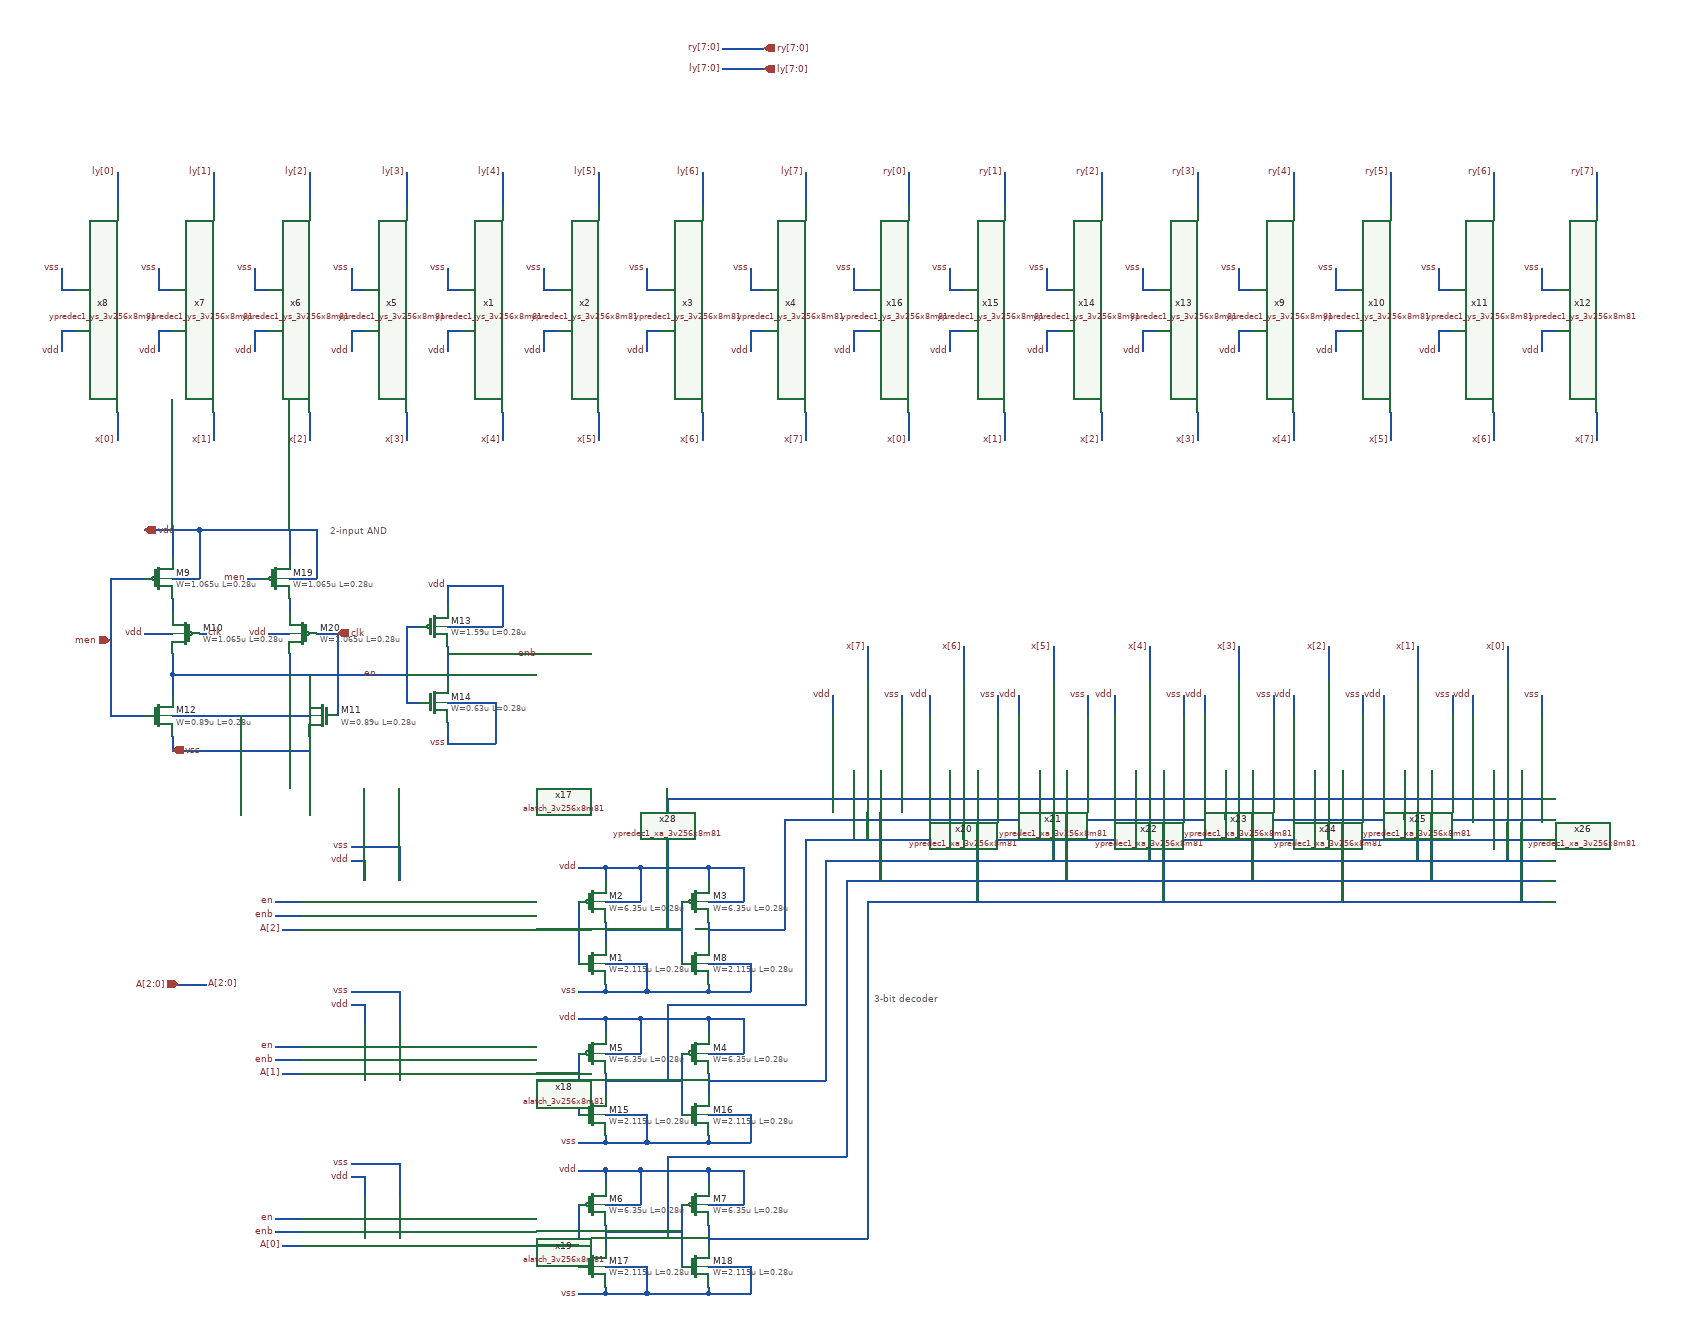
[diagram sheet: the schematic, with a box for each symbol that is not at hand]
v {xschem version=3.4.6 file_version=1.2}
G {}
K {}
V {}
S {}
E {}
T {2-input AND} -10 310 0 0 0.4 0.4 {}
T {3-bit decoder} 780 990 0 0 0.4 0.4 {}
N 1830 -200 1830 -150 {lab=ry[7]}
N 1680 -200 1680 -150 {lab=ry[6]}
N 1530 -200 1530 -150 {lab=ry[5]}
N 1390 -200 1390 -150 {lab=ry[4]}
N 1250 -200 1250 -150 {lab=ry[3]}
N 1110 -200 1110 -150 {lab=ry[2]}
N 970 -200 970 -150 {lab=ry[1]}
N 830 -200 830 -150 {lab=ry[0]}
N 680 -200 680 -150 {lab=ly[7]}
N 530 -200 530 -150 {lab=ly[6]}
N 380 -200 380 -150 {lab=ly[5]}
N 240 -200 240 -150 {lab=ly[4]}
N 100 -200 100 -150 {lab=ly[3]}
N -40 -200 -40 -150 {lab=ly[2]}
N -180 -200 -180 -150 {lab=ly[1]}
N -320 -200 -320 -150 {lab=ly[0]}
N -400 -30 -380 -30 {lab=vss}
N -400 -60 -400 -30 {lab=vss}
N -400 30 -380 30 {lab=vdd}
N -400 30 -400 60 {lab=vdd}
N -260 -30 -240 -30 {lab=vss}
N -260 -60 -260 -30 {lab=vss}
N -260 30 -240 30 {lab=vdd}
N -260 30 -260 60 {lab=vdd}
N -120 -30 -100 -30 {lab=vss}
N -120 -60 -120 -30 {lab=vss}
N -120 30 -100 30 {lab=vdd}
N -120 30 -120 60 {lab=vdd}
N 20 -30 40 -30 {lab=vss}
N 20 -60 20 -30 {lab=vss}
N 20 30 40 30 {lab=vdd}
N 20 30 20 60 {lab=vdd}
N 160 -30 180 -30 {lab=vss}
N 160 -60 160 -30 {lab=vss}
N 160 30 180 30 {lab=vdd}
N 160 30 160 60 {lab=vdd}
N 300 -30 320 -30 {lab=vss}
N 300 -60 300 -30 {lab=vss}
N 300 30 320 30 {lab=vdd}
N 300 30 300 60 {lab=vdd}
N 450 -30 470 -30 {lab=vss}
N 450 -60 450 -30 {lab=vss}
N 450 30 470 30 {lab=vdd}
N 450 30 450 60 {lab=vdd}
N 600 -30 620 -30 {lab=vss}
N 600 -60 600 -30 {lab=vss}
N 600 30 620 30 {lab=vdd}
N 600 30 600 60 {lab=vdd}
N 750 -30 770 -30 {lab=vss}
N 750 -60 750 -30 {lab=vss}
N 750 30 770 30 {lab=vdd}
N 750 30 750 60 {lab=vdd}
N 890 -30 910 -30 {lab=vss}
N 890 -60 890 -30 {lab=vss}
N 890 30 910 30 {lab=vdd}
N 890 30 890 60 {lab=vdd}
N 1030 -30 1050 -30 {lab=vss}
N 1030 -60 1030 -30 {lab=vss}
N 1030 30 1050 30 {lab=vdd}
N 1030 30 1030 60 {lab=vdd}
N 1170 -30 1190 -30 {lab=vss}
N 1170 -60 1170 -30 {lab=vss}
N 1170 30 1190 30 {lab=vdd}
N 1170 30 1170 60 {lab=vdd}
N 1310 -30 1330 -30 {lab=vss}
N 1310 -60 1310 -30 {lab=vss}
N 1310 30 1330 30 {lab=vdd}
N 1310 30 1310 60 {lab=vdd}
N 1450 -30 1470 -30 {lab=vss}
N 1450 -60 1450 -30 {lab=vss}
N 1450 30 1470 30 {lab=vdd}
N 1450 30 1450 60 {lab=vdd}
N 1600 -30 1620 -30 {lab=vss}
N 1600 -60 1600 -30 {lab=vss}
N 1600 30 1620 30 {lab=vdd}
N 1600 30 1600 60 {lab=vdd}
N 1750 -30 1770 -30 {lab=vss}
N 1750 -60 1750 -30 {lab=vss}
N 1750 30 1770 30 {lab=vdd}
N 1750 30 1750 60 {lab=vdd}
N -80 900 -50 900 {lab=A[2]}
N -80 1110 -50 1110 {lab=A[1]}
N -230 980 -190 980 {lab=A[2:0]}
N 770 490 770 540 {lab=x[7]}
N 910 490 910 540 {lab=x[6]}
N 1040 490 1040 540 {lab=x[5]}
N 1180 490 1180 540 {lab=x[4]}
N 350 860 350 950 {lab=#net1}
N 390 810 390 830 {lab=vdd}
N 390 810 440 810 {lab=vdd}
N 440 810 440 860 {lab=vdd}
N 390 860 440 860 {lab=vdd}
N 390 950 450 950 {lab=vss}
N 450 950 450 990 {lab=vss}
N 390 990 450 990 {lab=vss}
N 390 980 390 990 {lab=vss}
N 390 890 390 920 {lab=#net2}
N 390 900 500 900 {lab=#net2}
N 500 860 500 950 {lab=#net2}
N 540 810 540 830 {lab=vdd}
N 540 810 590 810 {lab=vdd}
N 590 810 590 860 {lab=vdd}
N 540 860 590 860 {lab=vdd}
N 540 950 600 950 {lab=vss}
N 600 950 600 990 {lab=vss}
N 540 990 600 990 {lab=vss}
N 540 980 540 990 {lab=vss}
N 540 890 540 920 {lab=#net3}
N 540 900 650 900 {lab=#net3}
N 160 900 350 900 {lab=#net1}
N 440 810 540 810 {lab=vdd}
N 450 990 540 990 {lab=vss}
N 350 990 390 990 {lab=vss}
N 350 810 390 810 {lab=vdd}
N 350 1080 350 1170 {lab=#net4}
N 390 1030 390 1050 {lab=vdd}
N 390 1030 440 1030 {lab=vdd}
N 440 1030 440 1080 {lab=vdd}
N 390 1080 440 1080 {lab=vdd}
N 390 1170 450 1170 {lab=vss}
N 450 1170 450 1210 {lab=vss}
N 390 1210 450 1210 {lab=vss}
N 390 1200 390 1210 {lab=vss}
N 390 1110 390 1140 {lab=#net5}
N 390 1120 500 1120 {lab=#net5}
N 500 1080 500 1170 {lab=#net5}
N 540 1030 540 1050 {lab=vdd}
N 540 1030 590 1030 {lab=vdd}
N 590 1030 590 1080 {lab=vdd}
N 540 1080 590 1080 {lab=vdd}
N 540 1170 600 1170 {lab=vss}
N 600 1170 600 1210 {lab=vss}
N 540 1210 600 1210 {lab=vss}
N 540 1200 540 1210 {lab=vss}
N 540 1110 540 1140 {lab=#net6}
N 540 1120 650 1120 {lab=#net6}
N 440 1030 540 1030 {lab=vdd}
N 450 1210 540 1210 {lab=vss}
N 350 1210 390 1210 {lab=vss}
N 350 1030 390 1030 {lab=vdd}
N 160 1110 350 1110 {lab=#net4}
N -90 860 -50 860 {lab=en}
N -90 1070 -50 1070 {lab=en}
N -90 880 -50 880 {lab=enb}
N -90 1090 -50 1090 {lab=enb}
N 160 490 160 540 {lab=enb}
N 100 460 120 460 {lab=en}
N 100 460 100 570 {lab=en}
N 100 570 120 570 {lab=en}
N 160 500 260 500 {lab=enb}
N 160 600 160 630 {lab=vss}
N 160 630 230 630 {lab=vss}
N 230 570 230 630 {lab=vss}
N 160 570 230 570 {lab=vss}
N 160 400 160 430 {lab=vdd}
N 160 400 240 400 {lab=vdd}
N 240 400 240 460 {lab=vdd}
N 160 460 240 460 {lab=vdd}
N 40 800 40 830 {lab=vdd}
N 20 800 40 800 {lab=vdd}
N 90 780 90 830 {lab=vss}
N 20 780 90 780 {lab=vss}
N 40 1010 40 1040 {lab=vdd}
N 20 1010 40 1010 {lab=vdd}
N 90 990 90 1040 {lab=vss}
N 20 990 90 990 {lab=vss}
N 720 560 720 590 {lab=vdd}
N 820 560 820 590 {lab=vss}
N 860 560 860 590 {lab=vdd}
N 960 560 960 590 {lab=vss}
N 990 560 990 590 {lab=vdd}
N 1090 560 1090 590 {lab=vss}
N 1130 560 1130 590 {lab=vdd}
N 1230 560 1230 590 {lab=vss}
N -240 420 -240 440 {lab=#net7}
N -240 320 -240 360 {lab=vdd}
N -240 390 -200 390 {lab=vdd}
N -200 320 -200 390 {lab=vdd}
N -280 320 -200 320 {lab=vdd}
N -330 390 -330 590 {lab=men}
N -240 620 -240 640 {lab=vss}
N -240 640 -40 640 {lab=vss}
N -40 620 -40 640 {lab=vss}
N -240 590 -40 590 {lab=vss}
N -140 590 -140 640 {lab=vss}
N 0 470 0 590 {lab=clk}
N -240 530 -240 560 {lab=en}
N -240 530 100 530 {lab=en}
N -40 530 -40 560 {lab=en}
N -240 500 -240 530 {lab=en}
N 480 710 480 900 {lab=#net2}
N 650 740 650 900 {lab=#net3}
N 480 1010 480 1120 {lab=#net5}
N 480 1010 680 1010 {lab=#net5}
N 680 770 680 1010 {lab=#net5}
N 650 1120 710 1120 {lab=#net6}
N 710 810 710 1120 {lab=#net6}
N 710 800 710 810 {lab=#net6}
N 560 -350 620 -350 {lab=ly[7:0]}
N -80 1360 -50 1360 {lab=A[0]}
N -90 1320 -50 1320 {lab=en}
N -90 1340 -50 1340 {lab=enb}
N 40 1260 40 1290 {lab=vdd}
N 20 1260 40 1260 {lab=vdd}
N 90 1240 90 1290 {lab=vss}
N 20 1240 90 1240 {lab=vss}
N 350 1300 350 1390 {lab=#net8}
N 390 1250 390 1270 {lab=vdd}
N 390 1250 440 1250 {lab=vdd}
N 440 1250 440 1300 {lab=vdd}
N 390 1300 440 1300 {lab=vdd}
N 390 1390 450 1390 {lab=vss}
N 450 1390 450 1430 {lab=vss}
N 390 1430 450 1430 {lab=vss}
N 390 1420 390 1430 {lab=vss}
N 390 1330 390 1360 {lab=#net9}
N 390 1340 500 1340 {lab=#net9}
N 500 1300 500 1390 {lab=#net9}
N 540 1250 540 1270 {lab=vdd}
N 540 1250 590 1250 {lab=vdd}
N 590 1250 590 1300 {lab=vdd}
N 540 1300 590 1300 {lab=vdd}
N 540 1390 600 1390 {lab=vss}
N 600 1390 600 1430 {lab=vss}
N 540 1430 600 1430 {lab=vss}
N 540 1420 540 1430 {lab=vss}
N 540 1330 540 1360 {lab=#net10}
N 440 1250 540 1250 {lab=vdd}
N 450 1430 540 1430 {lab=vss}
N 350 1430 390 1430 {lab=vss}
N 350 1250 390 1250 {lab=vdd}
N 160 1360 350 1360 {lab=#net8}
N 480 1230 480 1340 {lab=#net9}
N 740 830 740 1230 {lab=#net9}
N 480 1230 740 1230 {lab=#net9}
N 770 860 770 1350 {lab=#net10}
N 540 1350 770 1350 {lab=#net10}
N 1310 490 1310 540 {lab=x[3]}
N 1260 560 1260 590 {lab=vdd}
N 1360 560 1360 590 {lab=vss}
N 1440 490 1440 540 {lab=x[2]}
N 1390 560 1390 590 {lab=vdd}
N 1490 560 1490 590 {lab=vss}
N 1570 490 1570 540 {lab=x[1]}
N 1520 560 1520 590 {lab=vdd}
N 1620 560 1620 590 {lab=vss}
N 1700 490 1700 540 {lab=x[0]}
N 1650 560 1650 590 {lab=vdd}
N 1750 560 1750 590 {lab=vss}
N 770 860 1750 860 {lab=#net10}
N 740 830 1750 830 {lab=#net9}
N 710 800 1750 800 {lab=#net6}
N 680 770 1750 770 {lab=#net5}
N 650 740 1750 740 {lab=#net3}
N 480 710 1750 710 {lab=#net2}
N 750 670 750 710 {lab=#net2}
N 770 670 770 770 {lab=#net5}
N 790 670 790 830 {lab=#net9}
N 890 670 890 710 {lab=#net2}
N 910 670 910 770 {lab=#net5}
N 930 670 930 860 {lab=#net10}
N 1020 670 1020 710 {lab=#net2}
N 1040 670 1040 800 {lab=#net6}
N 1060 670 1060 830 {lab=#net9}
N 1160 670 1160 710 {lab=#net2}
N 1180 670 1180 800 {lab=#net6}
N 1200 670 1200 860 {lab=#net10}
N 1290 670 1290 740 {lab=#net3}
N 1420 670 1420 740 {lab=#net3}
N 1550 670 1550 740 {lab=#net3}
N 1680 670 1680 740 {lab=#net3}
N 1310 670 1310 770 {lab=#net5}
N 1330 670 1330 830 {lab=#net9}
N 1440 670 1440 770 {lab=#net5}
N 1460 670 1460 860 {lab=#net10}
N 1570 670 1570 800 {lab=#net6}
N 1590 670 1590 830 {lab=#net9}
N 1700 670 1700 800 {lab=#net6}
N 1720 670 1720 860 {lab=#net10}
N 560 -380 620 -380 {lab=ry[7:0]}
N 680 150 680 190 {lab=x[7]}
N 530 150 530 190 {lab=x[6]}
N 380 150 380 190 {lab=x[5]}
N 240 150 240 190 {lab=x[4]}
N 100 150 100 190 {lab=x[3]}
N -40 150 -40 190 {lab=x[2]}
N -180 150 -180 190 {lab=x[1]}
N -320 150 -320 190 {lab=x[0]}
N 1830 150 1830 190 {lab=x[7]}
N 1680 150 1680 190 {lab=x[6]}
N 1530 150 1530 190 {lab=x[5]}
N 1390 150 1390 190 {lab=x[4]}
N 1250 150 1250 190 {lab=x[3]}
N 1110 150 1110 190 {lab=x[2]}
N 970 150 970 190 {lab=x[1]}
N 830 150 830 190 {lab=x[0]}
N -280 470 -240 470 {lab=vdd}
N -330 590 -280 590 {lab=men}
N -330 390 -280 390 {lab=men}
N -70 420 -70 440 {lab=#net11}
N -70 320 -70 360 {lab=vdd}
N -70 390 -30 390 {lab=vdd}
N -30 320 -30 390 {lab=vdd}
N -130 390 -110 390 {lab=men}
N -200 470 -190 470 {lab=clk}
N -100 470 -70 470 {lab=vdd}
N -70 500 -70 530 {lab=en}
N -200 320 -30 320 {lab=vdd}
N -30 470 -0 470 {lab=clk}
C {ypredec1_ys_3v256x8m81.sym} 230 0 3 0 {name=x1}
C {ypredec1_ys_3v256x8m81.sym} 370 0 3 0 {name=x2}
C {ypredec1_ys_3v256x8m81.sym} 520 0 3 0 {name=x3}
C {ypredec1_ys_3v256x8m81.sym} 670 0 3 0 {name=x4}
C {ypredec1_ys_3v256x8m81.sym} 90 0 3 0 {name=x5}
C {ypredec1_ys_3v256x8m81.sym} -50 0 3 0 {name=x6}
C {ypredec1_ys_3v256x8m81.sym} -190 0 3 0 {name=x7}
C {ypredec1_ys_3v256x8m81.sym} -330 0 3 0 {name=x8}
C {ypredec1_ys_3v256x8m81.sym} 1380 0 3 0 {name=x9}
C {ypredec1_ys_3v256x8m81.sym} 1520 0 3 0 {name=x10}
C {ypredec1_ys_3v256x8m81.sym} 1670 0 3 0 {name=x11}
C {ypredec1_ys_3v256x8m81.sym} 1820 0 3 0 {name=x12}
C {ypredec1_ys_3v256x8m81.sym} 1240 0 3 0 {name=x13}
C {ypredec1_ys_3v256x8m81.sym} 1100 0 3 0 {name=x14}
C {ypredec1_ys_3v256x8m81.sym} 960 0 3 0 {name=x15}
C {ypredec1_ys_3v256x8m81.sym} 820 0 3 0 {name=x16}
C {lab_pin.sym} 1830 -200 1 0 {name=p1 sig_type=std_logic lab=ry[7]}
C {lab_pin.sym} 1680 -200 1 0 {name=p2 sig_type=std_logic lab=ry[6]}
C {lab_pin.sym} 1530 -200 1 0 {name=p3 sig_type=std_logic lab=ry[5]}
C {lab_pin.sym} 1390 -200 1 0 {name=p4 sig_type=std_logic lab=ry[4]}
C {lab_pin.sym} 1250 -200 1 0 {name=p5 sig_type=std_logic lab=ry[3]}
C {lab_pin.sym} 1110 -200 1 0 {name=p6 sig_type=std_logic lab=ry[2]}
C {lab_pin.sym} 970 -200 1 0 {name=p7 sig_type=std_logic lab=ry[1]}
C {lab_pin.sym} 830 -200 1 0 {name=p8 sig_type=std_logic lab=ry[0]}
C {lab_pin.sym} 680 -200 1 0 {name=p9 sig_type=std_logic lab=ly[7]}
C {lab_pin.sym} 530 -200 1 0 {name=p10 sig_type=std_logic lab=ly[6]}
C {lab_pin.sym} 380 -200 1 0 {name=p11 sig_type=std_logic lab=ly[5]}
C {lab_pin.sym} 240 -200 1 0 {name=p12 sig_type=std_logic lab=ly[4]}
C {lab_pin.sym} 100 -200 1 0 {name=p13 sig_type=std_logic lab=ly[3]}
C {lab_pin.sym} -40 -200 1 0 {name=p14 sig_type=std_logic lab=ly[2]}
C {lab_pin.sym} -180 -200 1 0 {name=p15 sig_type=std_logic lab=ly[1]}
C {lab_pin.sym} -320 -200 1 0 {name=p16 sig_type=std_logic lab=ly[0]}
C {lab_pin.sym} -400 -60 1 0 {name=p17 sig_type=std_logic lab=vss}
C {lab_pin.sym} -400 60 3 0 {name=p18 sig_type=std_logic lab=vdd}
C {lab_pin.sym} -260 -60 1 0 {name=p19 sig_type=std_logic lab=vss}
C {lab_pin.sym} -260 60 3 0 {name=p20 sig_type=std_logic lab=vdd}
C {lab_pin.sym} -120 -60 1 0 {name=p21 sig_type=std_logic lab=vss}
C {lab_pin.sym} -120 60 3 0 {name=p22 sig_type=std_logic lab=vdd}
C {lab_pin.sym} 20 -60 1 0 {name=p23 sig_type=std_logic lab=vss}
C {lab_pin.sym} 20 60 3 0 {name=p24 sig_type=std_logic lab=vdd}
C {lab_pin.sym} 160 -60 1 0 {name=p25 sig_type=std_logic lab=vss}
C {lab_pin.sym} 160 60 3 0 {name=p26 sig_type=std_logic lab=vdd}
C {lab_pin.sym} 300 -60 1 0 {name=p27 sig_type=std_logic lab=vss}
C {lab_pin.sym} 300 60 3 0 {name=p28 sig_type=std_logic lab=vdd}
C {lab_pin.sym} 450 -60 1 0 {name=p29 sig_type=std_logic lab=vss}
C {lab_pin.sym} 450 60 3 0 {name=p30 sig_type=std_logic lab=vdd}
C {lab_pin.sym} 600 -60 1 0 {name=p31 sig_type=std_logic lab=vss}
C {lab_pin.sym} 600 60 3 0 {name=p32 sig_type=std_logic lab=vdd}
C {lab_pin.sym} 750 -60 1 0 {name=p33 sig_type=std_logic lab=vss}
C {lab_pin.sym} 750 60 3 0 {name=p34 sig_type=std_logic lab=vdd}
C {lab_pin.sym} 890 -60 1 0 {name=p35 sig_type=std_logic lab=vss}
C {lab_pin.sym} 890 60 3 0 {name=p36 sig_type=std_logic lab=vdd}
C {lab_pin.sym} 1030 -60 1 0 {name=p37 sig_type=std_logic lab=vss}
C {lab_pin.sym} 1030 60 3 0 {name=p38 sig_type=std_logic lab=vdd}
C {lab_pin.sym} 1170 -60 1 0 {name=p39 sig_type=std_logic lab=vss}
C {lab_pin.sym} 1170 60 3 0 {name=p40 sig_type=std_logic lab=vdd}
C {lab_pin.sym} 1310 -60 1 0 {name=p41 sig_type=std_logic lab=vss}
C {lab_pin.sym} 1310 60 3 0 {name=p42 sig_type=std_logic lab=vdd}
C {lab_pin.sym} 1450 -60 1 0 {name=p43 sig_type=std_logic lab=vss}
C {lab_pin.sym} 1450 60 3 0 {name=p44 sig_type=std_logic lab=vdd}
C {lab_pin.sym} 1600 -60 1 0 {name=p45 sig_type=std_logic lab=vss}
C {lab_pin.sym} 1600 60 3 0 {name=p46 sig_type=std_logic lab=vdd}
C {lab_pin.sym} 1750 -60 1 0 {name=p47 sig_type=std_logic lab=vss}
C {lab_pin.sym} 1750 60 3 0 {name=p48 sig_type=std_logic lab=vdd}
C {alatch_3v256x8m81.sym} 100 880 0 0 {name=x17}
C {alatch_3v256x8m81.sym} 100 1090 0 0 {name=x18}
C {lab_pin.sym} -80 900 0 0 {name=p49 sig_type=std_logic lab=A[2]}
C {lab_pin.sym} -80 1110 0 0 {name=p50 sig_type=std_logic lab=A[1]}
C {ipin.sym} -230 980 0 0 {name=p51 lab=A[2:0]}
C {lab_pin.sym} -190 980 0 1 {name=p52 sig_type=std_logic lab=A[2:0]}
C {lab_pin.sym} 770 490 1 0 {name=p53 sig_type=std_logic lab=x[7]}
C {lab_pin.sym} 910 490 1 0 {name=p54 sig_type=std_logic lab=x[6]}
C {lab_pin.sym} 1040 490 1 0 {name=p55 sig_type=std_logic lab=x[5]}
C {lab_pin.sym} 1180 490 1 0 {name=p56 sig_type=std_logic lab=x[4]}
C {symbols/nfet_03v3.sym} 370 950 0 0 {name=M1
L=0.28u
W=2.115u
nf=1
m=1
ad="'int((nf+1)/2) * W/nf * 0.18u'"
pd="'2*int((nf+1)/2) * (W/nf + 0.18u)'"
as="'int((nf+2)/2) * W/nf * 0.18u'"
ps="'2*int((nf+2)/2) * (W/nf + 0.18u)'"
nrd="'0.18u / W'" nrs="'0.18u / W'"
sa=0 sb=0 sd=0
model=nfet_03v3
spiceprefix=X
}
C {symbols/pfet_03v3.sym} 370 860 0 0 {name=M2
L=0.28u
W=6.35u
nf=1
m=1
ad="'int((nf+1)/2) * W/nf * 0.18u'"
pd="'2*int((nf+1)/2) * (W/nf + 0.18u)'"
as="'int((nf+2)/2) * W/nf * 0.18u'"
ps="'2*int((nf+2)/2) * (W/nf + 0.18u)'"
nrd="'0.18u / W'" nrs="'0.18u / W'"
sa=0 sb=0 sd=0
model=pfet_03v3
spiceprefix=X
}
C {lab_pin.sym} 350 810 0 0 {name=p57 sig_type=std_logic lab=vdd}
C {lab_pin.sym} 350 990 0 0 {name=p58 sig_type=std_logic lab=vss}
C {lab_pin.sym} 350 1030 0 0 {name=p59 sig_type=std_logic lab=vdd}
C {lab_pin.sym} 350 1210 0 0 {name=p60 sig_type=std_logic lab=vss}
C {symbols/pfet_03v3.sym} -260 390 0 0 {name=M9
L=0.28u
W=1.065u
nf=1
m=1
ad="'int((nf+1)/2) * W/nf * 0.18u'"
pd="'2*int((nf+1)/2) * (W/nf + 0.18u)'"
as="'int((nf+2)/2) * W/nf * 0.18u'"
ps="'2*int((nf+2)/2) * (W/nf + 0.18u)'"
nrd="'0.18u / W'" nrs="'0.18u / W'"
sa=0 sb=0 sd=0
model=pfet_03v3
spiceprefix=X
}
C {symbols/pfet_03v3.sym} -220 470 0 1 {name=M10
L=0.28u
W=1.065u
nf=1
m=1
ad="'int((nf+1)/2) * W/nf * 0.18u'"
pd="'2*int((nf+1)/2) * (W/nf + 0.18u)'"
as="'int((nf+2)/2) * W/nf * 0.18u'"
ps="'2*int((nf+2)/2) * (W/nf + 0.18u)'"
nrd="'0.18u / W'" nrs="'0.18u / W'"
sa=0 sb=0 sd=0
model=pfet_03v3
spiceprefix=X
}
C {symbols/nfet_03v3.sym} -20 590 0 1 {name=M11
L=0.28u
W=0.89u
nf=1
m=1
ad="'int((nf+1)/2) * W/nf * 0.18u'"
pd="'2*int((nf+1)/2) * (W/nf + 0.18u)'"
as="'int((nf+2)/2) * W/nf * 0.18u'"
ps="'2*int((nf+2)/2) * (W/nf + 0.18u)'"
nrd="'0.18u / W'" nrs="'0.18u / W'"
sa=0 sb=0 sd=0
model=nfet_03v3
spiceprefix=X
}
C {symbols/nfet_03v3.sym} -260 590 0 0 {name=M12
L=0.28u
W=0.89u
nf=1
m=1
ad="'int((nf+1)/2) * W/nf * 0.18u'"
pd="'2*int((nf+1)/2) * (W/nf + 0.18u)'"
as="'int((nf+2)/2) * W/nf * 0.18u'"
ps="'2*int((nf+2)/2) * (W/nf + 0.18u)'"
nrd="'0.18u / W'" nrs="'0.18u / W'"
sa=0 sb=0 sd=0
model=nfet_03v3
spiceprefix=X
}
C {ipin.sym} 0 470 0 1 {name=p61 lab=clk}
C {ipin.sym} -330 480 0 0 {name=p62 lab=men}
C {lab_pin.sym} -90 860 0 0 {name=p63 sig_type=std_logic lab=en}
C {lab_pin.sym} -90 1070 0 0 {name=p64 sig_type=std_logic lab=en}
C {lab_pin.sym} -90 880 0 0 {name=p65 sig_type=std_logic lab=enb}
C {lab_pin.sym} -90 1090 0 0 {name=p66 sig_type=std_logic lab=enb}
C {lab_wire.sym} 60 530 0 0 {name=p67 sig_type=std_logic lab=en}
C {symbols/pfet_03v3.sym} 140 460 0 0 {name=M13
L=0.28u
W=1.59u
nf=2
m=1
ad="'int((nf+1)/2) * W/nf * 0.18u'"
pd="'2*int((nf+1)/2) * (W/nf + 0.18u)'"
as="'int((nf+2)/2) * W/nf * 0.18u'"
ps="'2*int((nf+2)/2) * (W/nf + 0.18u)'"
nrd="'0.18u / W'" nrs="'0.18u / W'"
sa=0 sb=0 sd=0
model=pfet_03v3
spiceprefix=X
}
C {symbols/nfet_03v3.sym} 140 570 0 0 {name=M14
L=0.28u
W=0.63u
nf=1
m=1
ad="'int((nf+1)/2) * W/nf * 0.18u'"
pd="'2*int((nf+1)/2) * (W/nf + 0.18u)'"
as="'int((nf+2)/2) * W/nf * 0.18u'"
ps="'2*int((nf+2)/2) * (W/nf + 0.18u)'"
nrd="'0.18u / W'" nrs="'0.18u / W'"
sa=0 sb=0 sd=0
model=nfet_03v3
spiceprefix=X
}
C {lab_pin.sym} 260 500 0 1 {name=p68 sig_type=std_logic lab=enb}
C {lab_pin.sym} 160 400 0 0 {name=p69 sig_type=std_logic lab=vdd}
C {lab_pin.sym} 160 630 0 0 {name=p70 sig_type=std_logic lab=vss}
C {lab_pin.sym} 20 780 0 0 {name=p71 sig_type=std_logic lab=vss}
C {lab_pin.sym} 20 990 0 0 {name=p72 sig_type=std_logic lab=vss}
C {lab_pin.sym} 20 800 0 0 {name=p73 sig_type=std_logic lab=vdd}
C {lab_pin.sym} 20 1010 0 0 {name=p74 sig_type=std_logic lab=vdd}
C {lab_pin.sym} 720 560 1 0 {name=p75 sig_type=std_logic lab=vdd}
C {lab_pin.sym} 860 560 1 0 {name=p76 sig_type=std_logic lab=vdd}
C {lab_pin.sym} 990 560 1 0 {name=p77 sig_type=std_logic lab=vdd}
C {lab_pin.sym} 1130 560 1 0 {name=p78 sig_type=std_logic lab=vdd}
C {lab_pin.sym} 820 560 1 0 {name=p79 sig_type=std_logic lab=vss}
C {lab_pin.sym} 960 560 1 0 {name=p80 sig_type=std_logic lab=vss}
C {lab_pin.sym} 1090 560 1 0 {name=p81 sig_type=std_logic lab=vss}
C {lab_pin.sym} 1230 560 1 0 {name=p82 sig_type=std_logic lab=vss}
C {opin.sym} 620 -350 0 0 {name=p83 lab=ly[7:0]}
C {lab_pin.sym} 560 -350 0 0 {name=p84 sig_type=std_logic lab=ly[7:0]}
C {iopin.sym} -280 320 0 1 {name=p85 lab=vdd}
C {iopin.sym} -240 640 0 1 {name=p86 lab=vss}
C {alatch_3v256x8m81.sym} 100 1340 0 0 {name=x19}
C {lab_pin.sym} -80 1360 0 0 {name=p87 sig_type=std_logic lab=A[0]}
C {lab_pin.sym} -90 1320 0 0 {name=p88 sig_type=std_logic lab=en}
C {lab_pin.sym} -90 1340 0 0 {name=p89 sig_type=std_logic lab=enb}
C {lab_pin.sym} 20 1240 0 0 {name=p90 sig_type=std_logic lab=vss}
C {lab_pin.sym} 20 1260 0 0 {name=p91 sig_type=std_logic lab=vdd}
C {lab_pin.sym} 350 1250 0 0 {name=p92 sig_type=std_logic lab=vdd}
C {lab_pin.sym} 350 1430 0 0 {name=p93 sig_type=std_logic lab=vss}
C {lab_pin.sym} 1310 490 1 0 {name=p94 sig_type=std_logic lab=x[3]}
C {lab_pin.sym} 1260 560 1 0 {name=p95 sig_type=std_logic lab=vdd}
C {lab_pin.sym} 1360 560 1 0 {name=p96 sig_type=std_logic lab=vss}
C {lab_pin.sym} 1440 490 1 0 {name=p97 sig_type=std_logic lab=x[2]}
C {lab_pin.sym} 1390 560 1 0 {name=p98 sig_type=std_logic lab=vdd}
C {lab_pin.sym} 1490 560 1 0 {name=p99 sig_type=std_logic lab=vss}
C {lab_pin.sym} 1570 490 1 0 {name=p100 sig_type=std_logic lab=x[1]}
C {lab_pin.sym} 1520 560 1 0 {name=p101 sig_type=std_logic lab=vdd}
C {lab_pin.sym} 1620 560 1 0 {name=p102 sig_type=std_logic lab=vss}
C {lab_pin.sym} 1700 490 1 0 {name=p103 sig_type=std_logic lab=x[0]}
C {lab_pin.sym} 1650 560 1 0 {name=p104 sig_type=std_logic lab=vdd}
C {lab_pin.sym} 1750 560 1 0 {name=p105 sig_type=std_logic lab=vss}
C {opin.sym} 620 -380 0 0 {name=p106 lab=ry[7:0]}
C {lab_pin.sym} 560 -380 0 0 {name=p107 sig_type=std_logic lab=ry[7:0]}
C {lab_pin.sym} 680 190 3 0 {name=p108 sig_type=std_logic lab=x[7]}
C {lab_pin.sym} 530 190 3 0 {name=p109 sig_type=std_logic lab=x[6]}
C {lab_pin.sym} 380 190 3 0 {name=p110 sig_type=std_logic lab=x[5]}
C {lab_pin.sym} 240 190 3 0 {name=p111 sig_type=std_logic lab=x[4]}
C {lab_pin.sym} 100 190 3 0 {name=p112 sig_type=std_logic lab=x[3]}
C {lab_pin.sym} -40 190 3 0 {name=p113 sig_type=std_logic lab=x[2]}
C {lab_pin.sym} -180 190 3 0 {name=p114 sig_type=std_logic lab=x[1]}
C {lab_pin.sym} -320 190 3 0 {name=p115 sig_type=std_logic lab=x[0]}
C {lab_pin.sym} 1830 190 3 0 {name=p116 sig_type=std_logic lab=x[7]}
C {lab_pin.sym} 1680 190 3 0 {name=p117 sig_type=std_logic lab=x[6]}
C {lab_pin.sym} 1530 190 3 0 {name=p118 sig_type=std_logic lab=x[5]}
C {lab_pin.sym} 1390 190 3 0 {name=p119 sig_type=std_logic lab=x[4]}
C {lab_pin.sym} 1250 190 3 0 {name=p120 sig_type=std_logic lab=x[3]}
C {lab_pin.sym} 1110 190 3 0 {name=p121 sig_type=std_logic lab=x[2]}
C {lab_pin.sym} 970 190 3 0 {name=p122 sig_type=std_logic lab=x[1]}
C {lab_pin.sym} 830 190 3 0 {name=p123 sig_type=std_logic lab=x[0]}
C {symbols/pfet_03v3.sym} 520 860 0 0 {name=M3
L=0.28u
W=6.35u
nf=1
m=1
ad="'int((nf+1)/2) * W/nf * 0.18u'"
pd="'2*int((nf+1)/2) * (W/nf + 0.18u)'"
as="'int((nf+2)/2) * W/nf * 0.18u'"
ps="'2*int((nf+2)/2) * (W/nf + 0.18u)'"
nrd="'0.18u / W'" nrs="'0.18u / W'"
sa=0 sb=0 sd=0
model=pfet_03v3
spiceprefix=X
}
C {symbols/pfet_03v3.sym} 520 1080 0 0 {name=M4
L=0.28u
W=6.35u
nf=1
m=1
ad="'int((nf+1)/2) * W/nf * 0.18u'"
pd="'2*int((nf+1)/2) * (W/nf + 0.18u)'"
as="'int((nf+2)/2) * W/nf * 0.18u'"
ps="'2*int((nf+2)/2) * (W/nf + 0.18u)'"
nrd="'0.18u / W'" nrs="'0.18u / W'"
sa=0 sb=0 sd=0
model=pfet_03v3
spiceprefix=X
}
C {symbols/pfet_03v3.sym} 370 1080 0 0 {name=M5
L=0.28u
W=6.35u
nf=1
m=1
ad="'int((nf+1)/2) * W/nf * 0.18u'"
pd="'2*int((nf+1)/2) * (W/nf + 0.18u)'"
as="'int((nf+2)/2) * W/nf * 0.18u'"
ps="'2*int((nf+2)/2) * (W/nf + 0.18u)'"
nrd="'0.18u / W'" nrs="'0.18u / W'"
sa=0 sb=0 sd=0
model=pfet_03v3
spiceprefix=X
}
C {symbols/pfet_03v3.sym} 370 1300 0 0 {name=M6
L=0.28u
W=6.35u
nf=1
m=1
ad="'int((nf+1)/2) * W/nf * 0.18u'"
pd="'2*int((nf+1)/2) * (W/nf + 0.18u)'"
as="'int((nf+2)/2) * W/nf * 0.18u'"
ps="'2*int((nf+2)/2) * (W/nf + 0.18u)'"
nrd="'0.18u / W'" nrs="'0.18u / W'"
sa=0 sb=0 sd=0
model=pfet_03v3
spiceprefix=X
}
C {symbols/pfet_03v3.sym} 520 1300 0 0 {name=M7
L=0.28u
W=6.35u
nf=1
m=1
ad="'int((nf+1)/2) * W/nf * 0.18u'"
pd="'2*int((nf+1)/2) * (W/nf + 0.18u)'"
as="'int((nf+2)/2) * W/nf * 0.18u'"
ps="'2*int((nf+2)/2) * (W/nf + 0.18u)'"
nrd="'0.18u / W'" nrs="'0.18u / W'"
sa=0 sb=0 sd=0
model=pfet_03v3
spiceprefix=X
}
C {symbols/nfet_03v3.sym} 520 950 0 0 {name=M8
L=0.28u
W=2.115u
nf=1
m=1
ad="'int((nf+1)/2) * W/nf * 0.18u'"
pd="'2*int((nf+1)/2) * (W/nf + 0.18u)'"
as="'int((nf+2)/2) * W/nf * 0.18u'"
ps="'2*int((nf+2)/2) * (W/nf + 0.18u)'"
nrd="'0.18u / W'" nrs="'0.18u / W'"
sa=0 sb=0 sd=0
model=nfet_03v3
spiceprefix=X
}
C {symbols/nfet_03v3.sym} 370 1170 0 0 {name=M15
L=0.28u
W=2.115u
nf=1
m=1
ad="'int((nf+1)/2) * W/nf * 0.18u'"
pd="'2*int((nf+1)/2) * (W/nf + 0.18u)'"
as="'int((nf+2)/2) * W/nf * 0.18u'"
ps="'2*int((nf+2)/2) * (W/nf + 0.18u)'"
nrd="'0.18u / W'" nrs="'0.18u / W'"
sa=0 sb=0 sd=0
model=nfet_03v3
spiceprefix=X
}
C {symbols/nfet_03v3.sym} 520 1170 0 0 {name=M16
L=0.28u
W=2.115u
nf=1
m=1
ad="'int((nf+1)/2) * W/nf * 0.18u'"
pd="'2*int((nf+1)/2) * (W/nf + 0.18u)'"
as="'int((nf+2)/2) * W/nf * 0.18u'"
ps="'2*int((nf+2)/2) * (W/nf + 0.18u)'"
nrd="'0.18u / W'" nrs="'0.18u / W'"
sa=0 sb=0 sd=0
model=nfet_03v3
spiceprefix=X
}
C {symbols/nfet_03v3.sym} 370 1390 0 0 {name=M17
L=0.28u
W=2.115u
nf=1
m=1
ad="'int((nf+1)/2) * W/nf * 0.18u'"
pd="'2*int((nf+1)/2) * (W/nf + 0.18u)'"
as="'int((nf+2)/2) * W/nf * 0.18u'"
ps="'2*int((nf+2)/2) * (W/nf + 0.18u)'"
nrd="'0.18u / W'" nrs="'0.18u / W'"
sa=0 sb=0 sd=0
model=nfet_03v3
spiceprefix=X
}
C {symbols/nfet_03v3.sym} 520 1390 0 0 {name=M18
L=0.28u
W=2.115u
nf=1
m=1
ad="'int((nf+1)/2) * W/nf * 0.18u'"
pd="'2*int((nf+1)/2) * (W/nf + 0.18u)'"
as="'int((nf+2)/2) * W/nf * 0.18u'"
ps="'2*int((nf+2)/2) * (W/nf + 0.18u)'"
nrd="'0.18u / W'" nrs="'0.18u / W'"
sa=0 sb=0 sd=0
model=nfet_03v3
spiceprefix=X
}
C {lab_pin.sym} -280 470 0 0 {name=p124 sig_type=std_logic lab=vdd}
C {symbols/pfet_03v3.sym} -90 390 0 0 {name=M19
L=0.28u
W=1.065u
nf=1
m=1
ad="'int((nf+1)/2) * W/nf * 0.18u'"
pd="'2*int((nf+1)/2) * (W/nf + 0.18u)'"
as="'int((nf+2)/2) * W/nf * 0.18u'"
ps="'2*int((nf+2)/2) * (W/nf + 0.18u)'"
nrd="'0.18u / W'" nrs="'0.18u / W'"
sa=0 sb=0 sd=0
model=pfet_03v3
spiceprefix=X
}
C {symbols/pfet_03v3.sym} -50 470 0 1 {name=M20
L=0.28u
W=1.065u
nf=1
m=1
ad="'int((nf+1)/2) * W/nf * 0.18u'"
pd="'2*int((nf+1)/2) * (W/nf + 0.18u)'"
as="'int((nf+2)/2) * W/nf * 0.18u'"
ps="'2*int((nf+2)/2) * (W/nf + 0.18u)'"
nrd="'0.18u / W'" nrs="'0.18u / W'"
sa=0 sb=0 sd=0
model=pfet_03v3
spiceprefix=X
}
C {lab_pin.sym} -100 470 0 0 {name=p125 sig_type=std_logic lab=vdd}
C {lab_pin.sym} -130 390 0 0 {name=p126 sig_type=std_logic lab=men}
C {lab_pin.sym} -190 470 0 1 {name=p127 sig_type=std_logic lab=clk}
C {ypredec1_xa_3v256x8m81.sym} 770 560 3 0 {name=x28}
C {ypredec1_xa_3v256x8m81.sym} 910 560 3 0 {name=x20}
C {ypredec1_xa_3v256x8m81.sym} 1040 560 3 0 {name=x21}
C {ypredec1_xa_3v256x8m81.sym} 1180 560 3 0 {name=x22}
C {ypredec1_xa_3v256x8m81.sym} 1310 560 3 0 {name=x23}
C {ypredec1_xa_3v256x8m81.sym} 1440 560 3 0 {name=x24}
C {ypredec1_xa_3v256x8m81.sym} 1570 560 3 0 {name=x25}
C {ypredec1_xa_3v256x8m81.sym} 1700 560 3 0 {name=x26}
